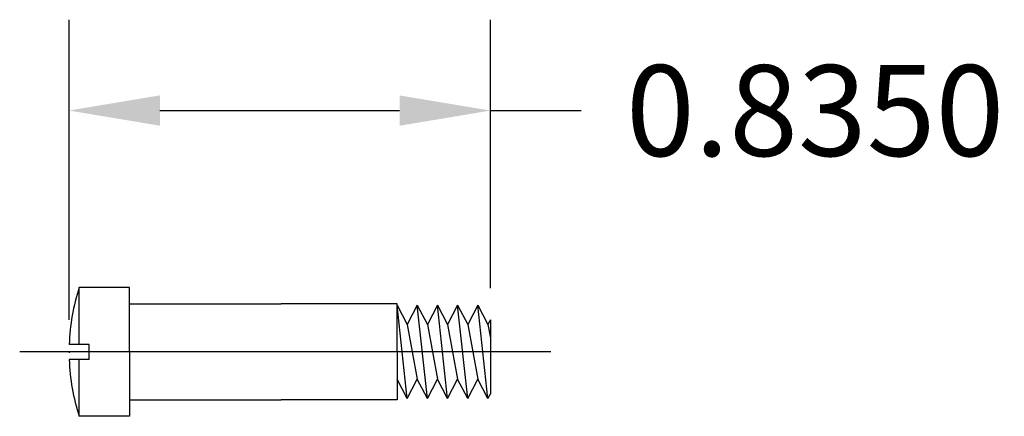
# Model space of a CAD drawing. Units: millimetres. Extents: x -0.75 to 1.2, y -0.13 to 0.66.
import ezdxf

# ---------------------------------------------------------------- set-up
doc = ezdxf.new("R2010")
doc.units = ezdxf.units.MM
doc.linetypes.add('ACAD_ISO10W100', pattern=[18, 12, -3, 0, -3])
doc.styles.get("Standard").update_dxf_attribs({"font": 'ARIAL.TTF'})
doc.dimstyles.get("Standard").update_dxf_attribs({"dimtxt": 0.18, "dimasz": 0.18, "dimexe": 0.18, "dimexo": 0.0625, "dimgap": 0.09, "dimtad": 0, "dimtih": 1, "dimtoh": 1, "dimdec": 4, "dimzin": 0, "dimdsep": 46, "dimtxsty": 'Standard', "dimcen": 0.09, "dimadec": 0, "dimazin": 0, "dimtfac": 1, "dimtdec": 4, "dimtofl": 0, "dimtmove": 0, "dimatfit": 3, "dimfxl": 0, "dimtolj": 1, "dimtzin": 0, "dimarcsym": 0})

# ---------------------------------------------------------------- blocks, each defined once
blk = doc.blocks.new('*D3')
at = {"color": 0, "lineweight": -2}
for p, q in [((-0.65, 0.0637), (-0.65, 0.6581)), ((0.185, 0.1262), (0.185, 0.6581)), ((-0.47, 0.4781), (0.005, 0.4781)), ((0.185, 0.4781), (0.365, 0.4781))]:
    blk.add_line(p, q, dxfattribs=at)
at = {"color": 0}
for points in [[(-0.47, 0.5081), (-0.47, 0.4481), (-0.65, 0.4781)], [(0.005, 0.5081), (0.005, 0.4481), (0.185, 0.4781)]]:
    blk.add_solid(points, dxfattribs=at)
at = {"layer": 'Defpoints', "color": 0}
for p in [(0.185, 0.4781), (0.185, 0.0637), (-0.65, 0.0012)]:
    blk.add_point(p, dxfattribs=at)
at = {"color": 0, "insert": (0.8283, 0.4781), "char_height": 0.18, "attachment_point": 5}
blk.add_mtext('\\A1;0.8350', dxfattribs=at)

msp = doc.modelspace()

# ---------------------------------------------------------------- linework, layer by layer
for p, q in [((-0.53, 0.1275), (-0.63, 0.1275)), ((-0.63, 0.015), (-0.63, 0.1275)), ((-0.53, 0), (-0.53, 0.1275)), ((-0.53, 0), (-0.53, 0.095)), ((-0.53, 0.095), (-0.23, 0.095)), ((0, 0.095), (-0.23, 0.095)), ((0, 0), (0, 0.095)), ((0, 0.0925), (0.02, 0.05408)), ((0.02, -0.0925), (0, 0.0925)), ((0.04, 0.0925), (0.02, 0.05408)), ((0.04, 0.0925), (0.06, 0.05408)), ((0.06, -0.0925), (0.04, 0.0925)), ((0.08, 0.0925), (0.06, 0.05408)), ((0.08, 0.0925), (0.1, 0.05408)), ((0.1, -0.0925), (0.08, 0.0925)), ((0.12, 0.0925), (0.1, 0.05408)), ((0.12, 0.0925), (0.14, 0.05408)), ((0.14, -0.0925), (0.12, 0.0925)), ((0.16, 0.0925), (0.14, 0.05408)), ((0.16, 0.0925), (0.18, 0.05408)), ((0.18, -0.0925), (0.16, 0.0925)), ((0.185, 0.06369), (0.18, 0.05408)), ((0.185, 0.06369), (0.185, -0.0829)), ((0.02, 0.05408), (0.04, -0.05408)), ((0.06, 0.05408), (0.08, -0.05408)), ((0.1, 0.05408), (0.12, -0.05408)), ((0.14, 0.05408), (0.16, -0.05408)), ((0.18, 0.05408), (0.185, 0.02704)), ((-0.61, 0.015), (-0.64973, 0.015)), ((-0.61, -0.015), (-0.61, 0.015)), ((-0.53, 0), (-0.53, -0.095)), ((-0.53, 0), (-0.53, -0.1275)), ((0, 0), (0, -0.095)), ((-0.61, -0.015), (-0.64973, -0.015)), ((-0.63, -0.1275), (-0.63, -0.015)), ((0.02, -0.0925), (0, -0.05408)), ((0.02, -0.0925), (0.04, -0.05408)), ((0.06, -0.0925), (0.04, -0.05408)), ((0.06, -0.0925), (0.08, -0.05408)), ((0.1, -0.0925), (0.08, -0.05408)), ((0.1, -0.0925), (0.12, -0.05408)), ((0.14, -0.0925), (0.12, -0.05408)), ((0.14, -0.0925), (0.16, -0.05408)), ((0.18, -0.0925), (0.16, -0.05408)), ((-0.53, -0.095), (-0.23, -0.095)), ((0, -0.095), (-0.23, -0.095)), ((0.18, -0.0925), (0.185, -0.0829)), ((-0.53, -0.1275), (-0.63, -0.1275))]:
    msp.add_line(p, q)
at = {"color": 1, "linetype": 'ACAD_ISO10W100'}
msp.add_line((0.3044, 0), (-0.74782, 0), dxfattribs=at)
for start, end in [(162.17015, 177.93562), (179.83113, 180.23514), (182.06438, 197.82985)]:
    msp.add_arc((-0.23359, 0), 0.41641, start, end)

# ---------------------------------------------------------------- dimensions: what is measured, and where the dimension line sits
dim = msp.add_linear_dim(base=(0.185, 0.4781), p1=(-0.65, 0.00123), p2=(0.185, 0.06369), dimstyle='Standard')
dim.commit()
dim.dimension.update_dxf_attribs({"geometry": '*D3', "text_midpoint": (0.82832, 0.4781)})

doc.saveas('drawing.dxf')
